VERSION 5.7 ;
  NOWIREEXTENSIONATPIN ON ;
  DIVIDERCHAR "/" ;
  BUSBITCHARS "[]" ;
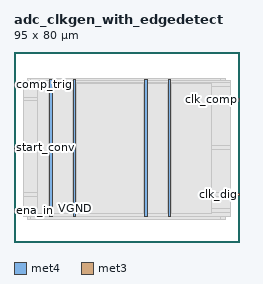
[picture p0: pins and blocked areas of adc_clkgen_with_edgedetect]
MACRO adc_clkgen_with_edgedetect
  CLASS BLOCK ;
  FOREIGN adc_clkgen_with_edgedetect ;
  ORIGIN 0.000 0.000 ;
  SIZE 95.000 BY 80.000 ;
  PIN VGND
    DIRECTION INOUT ;
    USE GROUND ;
    PORT
      LAYER met4 ;
        RECT 25.020 10.640 26.020 68.240 ;
    END
    PORT
      LAYER met4 ;
        RECT 65.020 10.640 66.020 68.240 ;
    END
  END VGND
  PIN VPWR
    DIRECTION INOUT ;
    USE POWER ;
    PORT
      LAYER met4 ;
        RECT 15.020 10.640 16.020 68.240 ;
    END
    PORT
      LAYER met4 ;
        RECT 55.020 10.640 56.020 68.240 ;
    END
  END VPWR
  PIN clk_comp
    DIRECTION OUTPUT TRISTATE ;
    USE SIGNAL ;
    PORT
      LAYER met3 ;
        RECT 91.000 59.880 95.000 60.480 ;
    END
  END clk_comp
  PIN clk_dig
    DIRECTION OUTPUT TRISTATE ;
    USE SIGNAL ;
    PORT
      LAYER met3 ;
        RECT 91.000 19.760 95.000 20.360 ;
    END
  END clk_dig
  PIN comp_trig
    DIRECTION INPUT ;
    USE SIGNAL ;
    PORT
      LAYER met3 ;
        RECT 0.000 66.000 4.000 66.600 ;
    END
  END comp_trig
  PIN ena_in
    DIRECTION INPUT ;
    USE SIGNAL ;
    PORT
      LAYER met3 ;
        RECT 0.000 12.960 4.000 13.560 ;
    END
  END ena_in
  PIN start_conv
    DIRECTION INPUT ;
    USE SIGNAL ;
    PORT
      LAYER met3 ;
        RECT 0.000 39.480 4.000 40.080 ;
    END
  END start_conv
  OBS
      LAYER li1 ;
        RECT 5.520 10.795 89.240 68.085 ;
      LAYER met1 ;
        RECT 5.520 9.560 89.240 68.980 ;
      LAYER met2 ;
        RECT 6.990 9.530 86.850 69.010 ;
      LAYER met3 ;
        RECT 4.000 67.000 91.000 68.165 ;
        RECT 4.400 65.600 91.000 67.000 ;
        RECT 4.000 60.880 91.000 65.600 ;
        RECT 4.000 59.480 90.600 60.880 ;
        RECT 4.000 40.480 91.000 59.480 ;
        RECT 4.400 39.080 91.000 40.480 ;
        RECT 4.000 20.760 91.000 39.080 ;
        RECT 4.000 19.360 90.600 20.760 ;
        RECT 4.000 13.960 91.000 19.360 ;
        RECT 4.400 12.560 91.000 13.960 ;
        RECT 4.000 10.715 91.000 12.560 ;
      LAYER met4 ;
        RECT 10.090 12.010 14.620 66.930 ;
        RECT 16.420 12.010 24.620 66.930 ;
        RECT 26.420 12.010 54.620 66.930 ;
        RECT 56.420 12.010 64.620 66.930 ;
        RECT 66.420 12.010 83.290 66.930 ;
  END
END adc_clkgen_with_edgedetect
END LIBRARY

